One B-rep face of a CAD part: STEP entity #312.
In plain terms, the planar face has unit normal (1, 0, 0).
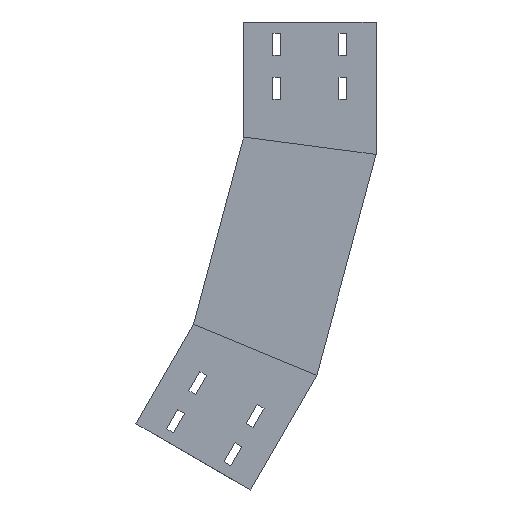
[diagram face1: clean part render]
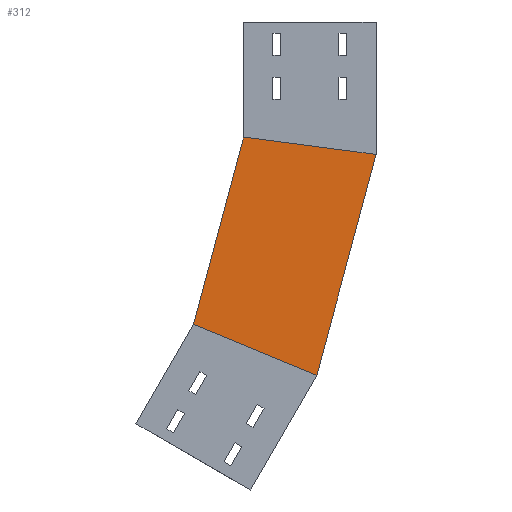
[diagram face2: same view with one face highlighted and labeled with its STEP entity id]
Its self-contained STEP definition (entity closure, numbers rounded to 3 decimals):
#183 = ORIENTED_EDGE ( 'NONE', *, *, #1381, .F. ) ;
#300 = DIRECTION ( 'NONE',  ( 0., 0., 1. ) ) ;
#312 = ADVANCED_FACE ( 'NONE', ( #994 ), #648, .F. ) ;
#316 = EDGE_CURVE ( 'NONE', #1547, #1101, #1739, .T. ) ;
#331 = DIRECTION ( 'NONE',  ( -1., 0., 0. ) ) ;
#355 = CARTESIAN_POINT ( 'NONE',  ( 0., 67.034, -400.175 ) ) ;
#393 = ORIENTED_EDGE ( 'NONE', *, *, #738, .T. ) ;
#521 = CARTESIAN_POINT ( 'NONE',  ( 0., 98.267, -387.238 ) ) ;
#549 = VECTOR ( 'NONE', #1759, 1000. ) ;
#648 = PLANE ( 'NONE',  #1678 ) ;
#672 = ORIENTED_EDGE ( 'NONE', *, *, #1488, .F. ) ;
#723 = LINE ( 'NONE', #521, #1215 ) ;
#738 = EDGE_CURVE ( 'NONE', #1101, #1096, #1134, .T. ) ;
#799 = CARTESIAN_POINT ( 'NONE',  ( 0., 0., -150. ) ) ;
#978 = VECTOR ( 'NONE', #1082, 1000. ) ;
#994 = FACE_OUTER_BOUND ( 'NONE', #1490, .T. ) ;
#1007 = DIRECTION ( 'NONE',  ( 0., -0.924, -0.383 ) ) ;
#1032 = CARTESIAN_POINT ( 'NONE',  ( 0., 150., -130.252 ) ) ;
#1056 = CARTESIAN_POINT ( 'NONE',  ( 0., 206.812, -342.277 ) ) ;
#1071 = CARTESIAN_POINT ( 'NONE',  ( 0., 144.889, -111.177 ) ) ;
#1082 = DIRECTION ( 'NONE',  ( 0., 0.259, -0.966 ) ) ;
#1091 = ORIENTED_EDGE ( 'NONE', *, *, #316, .T. ) ;
#1096 = VERTEX_POINT ( 'NONE', #355 ) ;
#1101 = VERTEX_POINT ( 'NONE', #799 ) ;
#1111 = DIRECTION ( 'NONE',  ( 0., -0.991, -0.131 ) ) ;
#1122 = CARTESIAN_POINT ( 'NONE',  ( 0., 19.411, -147.444 ) ) ;
#1134 = LINE ( 'NONE', #1270, #549 ) ;
#1215 = VECTOR ( 'NONE', #1007, 1000. ) ;
#1257 = CARTESIAN_POINT ( 'NONE',  ( 0., 0., -150. ) ) ;
#1270 = CARTESIAN_POINT ( 'NONE',  ( 0., 0., -150. ) ) ;
#1381 = EDGE_CURVE ( 'NONE', #1547, #1773, #1521, .T. ) ;
#1488 = EDGE_CURVE ( 'NONE', #1773, #1096, #723, .T. ) ;
#1490 = EDGE_LOOP ( 'NONE', ( #183, #1091, #393, #672 ) ) ;
#1521 = LINE ( 'NONE', #1071, #978 ) ;
#1547 = VERTEX_POINT ( 'NONE', #1032 ) ;
#1678 = AXIS2_PLACEMENT_3D ( 'NONE', #1257, #331, #300 ) ;
#1739 = LINE ( 'NONE', #1122, #1835 ) ;
#1759 = DIRECTION ( 'NONE',  ( 0., 0.259, -0.966 ) ) ;
#1773 = VERTEX_POINT ( 'NONE', #1056 ) ;
#1835 = VECTOR ( 'NONE', #1111, 1000. ) ;
